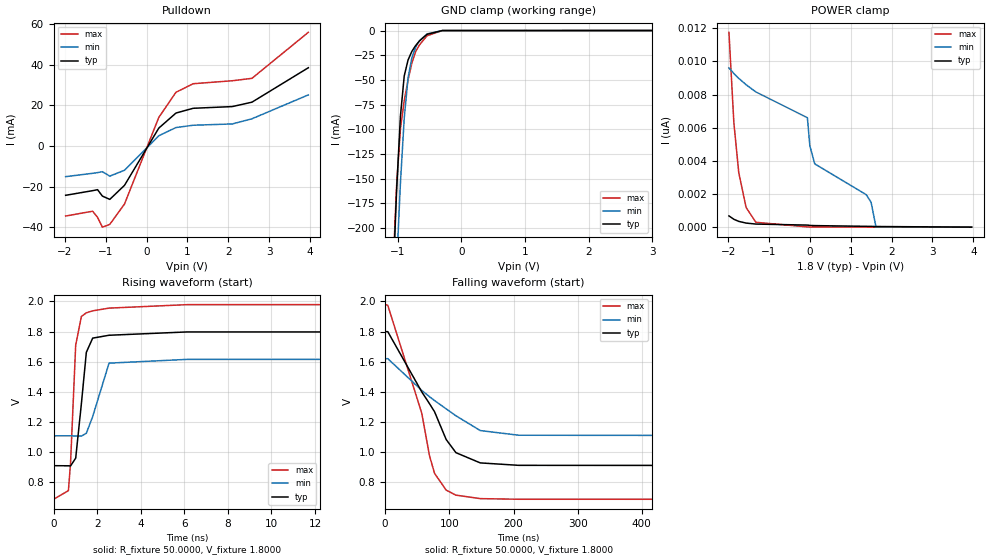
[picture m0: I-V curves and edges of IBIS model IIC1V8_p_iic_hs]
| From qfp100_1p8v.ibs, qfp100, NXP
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[Model] IIC1V8_p_iic_hs
|   Model IIC1V8_p_iic_hs
| This model was characterised for following simulation conditions:
| External (pad) voltage:
|   - Typ: 1.8V,   - Min: 1.62V,   - Max: 1.98V
| Library cells for typ/min/max conditions are connected as defined below:
|  IO - External Pad
|  A - Core Input
|  EN - Output Buffer Enable
|  BOOST - vdde
|  ECS - gnd
|  EGP - gnd
|  ENZI - vdd
|  EPD - gnd
|  EPUN - vdd
|  ZI - NC
|  ZIF - NC
|  gnd - gnd
|  gnde - gnde
|  vdd - vdd
|  vdde - vdde
| All other pins connected to ground
Model_type I/O_open_drain
Polarity   Non-Inverting
Enable   Active-Low
Vinl =   0.5400V
Vinh =   1.2600V
Vmeas =  0.9000V
Cref =   0.0F
Rref =   1000.000
Vref =   1.8000V
C_comp   3.6454pF   3.5038pF   3.7808pF
|C_comp_pullup   0.9524pF   0.9269pF   0.9624pF
|C_comp_pulldown   2.3410pF   2.4924pF   2.1971pF
[Model Spec]
| variable   typ   min   max
Vinh   0.5400V   0.4860V   0.5940V
Vinl   1.2600V   1.1340V   1.3860V
Vmeas   0.9000V   0.8100V   0.9900V
Vref   1.8000V   1.6200V   1.9800V
Cref   0.0F   0.0F   0.0F
Rref   1.0000k   1.0000k   1.0000k
[Temperature Range]   25.0000   0.1250k   -40.0000
[Voltage Range]   1.8000V   1.6200V   1.9800V
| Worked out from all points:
|   slope of the pulldown table from 0 to 0.27 V, typ, clamps not added: 33.4 ohm
|   GND clamp passes 1 mA (typ) near -0.44 V on its own axis
|   rising waveform, R_fixture 50.0000, V_fixture 1.8000: 20-80 % time 321ps typ, 491ps min, 237ps max; typ from 0.911 V to 1.8 V
|   falling waveform, R_fixture 50.0000, V_fixture 1.8000: 20-80 % time 66.9ns typ, 88.7ns min, 48.9ns max; typ from 1.8 V to 0.911 V
[Pulldown]
|Voltage   I(typ)   I(min)   I(max)
-1.98V    -24.22mA   -15.04mA   -34.42mA
-1.32V    -21.94mA   -13.4mA    -32.06mA
-1.2V     -21.45mA   -13.05mA   -35.06mA
-1.08V    -24.63mA   -12.6mA    -39.9mA
-900mV    -26.23mA   -14.78mA   -38.53mA
-540mV    -19.33mA   -11.9mA    -28.53mA
300mV     8.856mA    5.096mA    14.12mA
720mV     16.26mA    9.117mA    26.48mA
1.14V     18.6mA     10.26mA    30.69mA
2.1V      19.45mA    10.9mA     32.16mA
2.58V     21.61mA    13.44mA    33.34mA
3.96V     38.56mA    25.19mA    55.99mA
[GND_clamp]
|Voltage   I(typ)   I(min)   I(max)
-1.98V    -2.104A    -2.075A    -2.136A
-1.08V    -259.3mA   -333mA     -246.9mA
-1.02V    -161.8mA   -238.7mA   -157.1mA
-960mV    -86.74mA   -154.7mA   -99.46mA
-900mV    -45.95mA   -88.82mA   -71.05mA
-840mV    -29.9mA    -47.99mA   -50.25mA
-780mV    -21.15mA   -27.64mA   -32.98mA
-720mV    -15.16mA   -16.87mA   -21.26mA
-660mV    -10.56mA   -10.24mA   -14.56mA
-540mV    -3.788mA   -3.398mA   -5.292mA
-300mV    -15.94uA   -36uA      -16.34uA
3.96V     0A         0A         0A
[POWER_clamp]
|Voltage   I(typ)   I(min)   I(max)
-1.98V    679.6pA    9.61nA     11.76nA
-1.86V    475.2pA    9.277nA    6.313nA
-1.74V    349.2pA    8.982nA    3.292nA
-1.56V    245.6pA    8.597nA    1.186nA
-1.32V    186pA      8.161nA    293.2pA
-60mV     124.8pA    6.606nA    14.31pA
0V        105.5pA    4.916nA    11.81pA
120mV     93.21pA    3.82nA     10.91pA
1.38V     50pA       1.96nA     2.877pA
1.5V      45.28pA    1.501nA    2.149pA
1.62V     39.18pA    0A         1.42pA
3.96V     0A         0A         0A
[Ramp]
| variable   typ   min   max
dV/dt_r  0.5334/0.3209n   0.3066/0.4909n   0.7753/0.2369n
dV/dt_f  0.5334/66.9323n   0.3066/88.7325n   0.7753/48.9497n
R_load = 50.0000
[Rising Waveform]
R_fixture= 50.0000
V_fixture= 1.8000
V_fixture_min= 1.6200
V_fixture_max= 1.9800
|time   V(typ)   V(min)   V(max)
0s        911mV      1.109V     687.8mV
683.3ps   910.2mV    1.109V     745.5mV
780.5ps   909.1mV    1.109V     927.7mV
1.017ns   961.1mV    1.108V     1.71V
1.277ns   1.32V      1.107V     1.9V
1.506ns   1.663V     1.126V     1.925V
1.797ns   1.757V     1.237V     1.938V
2.547ns   1.776V     1.591V     1.956V
6.124ns   1.798V     1.616V     1.979V
1us       1.8V       1.62V      1.98V
[Falling Waveform]
R_fixture= 50.0000
V_fixture= 1.8000
V_fixture_min= 1.6200
V_fixture_max= 1.9800
|time   V(typ)   V(min)   V(max)
0s        1.8V       1.62V      1.98V
4.033ns   1.8V       1.621V     1.975V
57.1ns    1.4V       1.41V      1.258V
68.97ns   1.323V     1.369V     978.6mV
76.93ns   1.269V     1.343V     860.5mV
95.01ns   1.085V     1.288V     749mV
110.3ns   997.3mV    1.242V     715.6mV
148.2ns   929.5mV    1.144V     692.6mV
208ns     913.4mV    1.113V     688.4mV
1us       911.1mV    1.109V     687.9mV
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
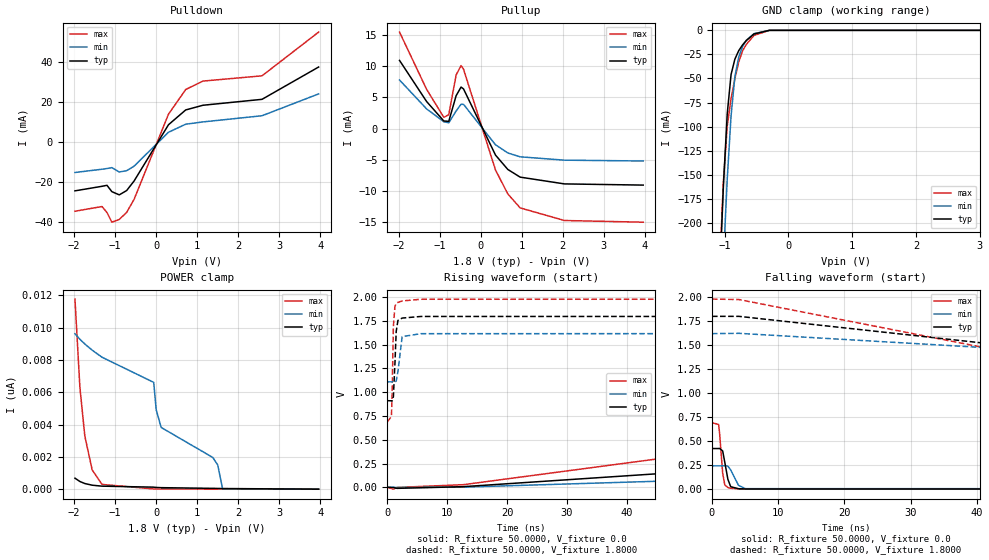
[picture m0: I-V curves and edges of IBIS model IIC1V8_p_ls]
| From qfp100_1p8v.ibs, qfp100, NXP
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[Model] IIC1V8_p_ls
|   Model IIC1V8_p_ls
| This model was characterised for following simulation conditions:
| External (pad) voltage:
|   - Typ: 1.8V,   - Min: 1.62V,   - Max: 1.98V
| Library cells for typ/min/max conditions are connected as defined below:
|  IO - External Pad
|  A - Core Input
|  EN - Output Buffer Enable
|  BOOST - vdde
|  EGP - vdd
|  EHS - gnd
|  ENZI - vdd
|  EPD - gnd
|  EPUN - vdd
|  ZI - NC
|  ZIF - NC
|  gnd - gnd
|  gnde - gnde
|  vdd - vdd
|  vdde - vdde
| All other pins connected to ground
Model_type I/O
Polarity   Non-Inverting
Enable   Active-Low
Vinl =   0.5400V
Vinh =   1.2600V
Vmeas =  0.9000V
Cref =   0.0F
Rref =   1.0000k
Vref =   0.0V
C_comp   3.6452pF   3.5037pF   3.7805pF
|C_comp_pullup   0.9521pF   0.9262pF   0.9623pF
|C_comp_pulldown   2.3411pF   2.4927pF   2.1971pF
[Model Spec]
| variable   typ   min   max
Vinh   0.5400V   0.4860V   0.5940V
Vinl   1.2600V   1.1340V   1.3860V
Vmeas   0.9000V   0.8100V   0.9900V
[Temperature Range]   25.0000   0.1250k   -40.0000
[Voltage Range]   1.8000V   1.6200V   1.9800V
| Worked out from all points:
|   slope of the pulldown table from 0 to 0.27 V, typ, clamps not added: 33.4 ohm
|   slope of the pullup table from 0 to 0.27 V, typ, clamps not added: 80.7 ohm
|   GND clamp passes 1 mA (typ) near -0.44 V on its own axis
|   rising waveform, R_fixture 50.0000, V_fixture 0.0: 20-80 % time 70.1ns typ, 82ns min, 57.1ns max; typ from 0 V to 0.423 V
|   rising waveform, R_fixture 50.0000, V_fixture 1.8000: 20-80 % time 319ps typ, 487ps min, 235ps max; typ from 0.911 V to 1.8 V
|   falling waveform, R_fixture 50.0000, V_fixture 0.0: 20-80 % time 672ps typ, 1.04ns min, 474ps max; typ from 0.423 V to 0 V
|   falling waveform, R_fixture 50.0000, V_fixture 1.8000: 20-80 % time 66.9ns typ, 88.7ns min, 49ns max; typ from 1.8 V to 0.911 V
[Pulldown]
|Voltage   I(typ)   I(min)   I(max)
-1.98V    -24.22mA   -15.04mA   -34.42mA
-1.32V    -21.94mA   -13.4mA    -32.06mA
-1.2V     -21.45mA   -13.05mA   -35.06mA
-1.08V    -24.63mA   -12.6mA    -39.9mA
-900mV    -26.23mA   -14.78mA   -38.53mA
-720mV    -24.07mA   -14.13mA   -34.99mA
-540mV    -19.33mA   -11.9mA    -28.53mA
300mV     8.856mA    5.096mA    14.12mA
720mV     16.26mA    9.117mA    26.48mA
1.14V     18.6mA     10.26mA    30.69mA
2.58V     21.56mA    13.35mA    33.32mA
3.96V     37.73mA    24.28mA    55.2mA
[Pullup]
|Voltage   I(typ)   I(min)   I(max)
-1.98V    10.95mA    7.799mA    15.5mA
-1.32V    4.346mA    3.159mA    6.304mA
-900mV    1.218mA    1.094mA    1.804mA
-780mV    1.156mA    929.2uA    2.224mA
-600mV    5.286mA    2.831mA    8.611mA
-480mV    6.667mA    3.906mA    10.12mA
-420mV    6.372mA    3.889mA    9.539mA
360mV     -4.265mA   -2.608mA   -6.666mA
660mV     -6.57mA    -3.917mA   -10.5mA
960mV     -7.8mA     -4.537mA   -12.74mA
2.04V     -8.889mA   -5.075mA   -14.77mA
3.96V     -9.081mA   -5.209mA   -15.04mA
[GND_clamp]
|Voltage   I(typ)   I(min)   I(max)
-1.98V    -2.104A    -2.075A    -2.136A
-1.08V    -259.3mA   -333mA     -246.9mA
-1.02V    -161.8mA   -238.7mA   -157.1mA
-960mV    -86.74mA   -154.7mA   -99.46mA
-900mV    -45.95mA   -88.82mA   -71.05mA
-840mV    -29.9mA    -47.99mA   -50.25mA
-780mV    -21.15mA   -27.64mA   -32.98mA
-720mV    -15.16mA   -16.87mA   -21.26mA
-660mV    -10.56mA   -10.24mA   -14.56mA
-540mV    -3.788mA   -3.398mA   -5.292mA
-300mV    -15.94uA   -36uA      -16.34uA
3.96V     0A         0A         0A
[POWER_clamp]
|Voltage   I(typ)   I(min)   I(max)
-1.98V    679.6pA    9.61nA     11.76nA
-1.86V    475.2pA    9.277nA    6.313nA
-1.74V    349.2pA    8.982nA    3.292nA
-1.56V    245.6pA    8.597nA    1.186nA
-1.32V    186pA      8.161nA    293.2pA
-60mV     124.8pA    6.606nA    14.31pA
0V        105.5pA    4.916nA    11.81pA
120mV     93.21pA    3.82nA     10.91pA
1.38V     50pA       1.96nA     2.877pA
1.5V      45.28pA    1.501nA    2.149pA
1.62V     39.18pA    0A         1.42pA
3.96V     0A         0A         0A
[Ramp]
| variable   typ   min   max
dV/dt_r  0.2539/70.1178n   0.1457/81.9302n   0.4150/57.0489n
dV/dt_f  0.5334/66.9358n   0.3066/88.6649n   0.7753/48.9538n
R_load = 50.0000
[Rising Waveform]
R_fixture= 50.0000
V_fixture= 0.0
V_fixture_min= 0.0
V_fixture_max= 0.0
|time   V(typ)   V(min)   V(max)
0s        602.8pV    52.95nV    41.9pV
1.012ns   -3.31mV    192.5uV    -19.98mV
1.632ns   -11.39mV   -2.738mV   -1.795mV
12.68ns   6.299mV    1.388mV    27.19mV
45.88ns   145.4mV    64.89mV    304.8mV
84.55ns   285.2mV    143.4mV    561.1mV
103.3ns   339.8mV    172mV      629.2mV
134ns     392.1mV    207.9mV    672.5mV
250.9ns   422.4mV    241.3mV    691.3mV
1us       423.2mV    242.8mV    691.7mV
[Rising Waveform]
R_fixture= 50.0000
V_fixture= 1.8000
V_fixture_min= 1.6200
V_fixture_max= 1.9800
|time   V(typ)   V(min)   V(max)
0s        911mV      1.109V     687.8mV
685.2ps   909.5mV    1.109V     745.1mV
787ps     907.1mV    1.109V     945.8mV
1.007ns   951.3mV    1.108V     1.694V
1.269ns   1.304V     1.105V     1.904V
1.479ns   1.639V     1.118V     1.932V
1.768ns   1.755V     1.218V     1.945V
2.476ns   1.78V      1.585V     1.96V
5.596ns   1.797V     1.616V     1.978V
1us       1.8V       1.62V      1.98V
[Falling Waveform]
R_fixture= 50.0000
V_fixture= 0.0
V_fixture_min= 0.0
V_fixture_max= 0.0
|time   V(typ)   V(min)   V(max)
0s        423.2mV    242.8mV    691.7mV
1.011ns   423.2mV    242.8mV    674.4mV
1.154ns   424.5mV    242.8mV    586.3mV
1.621ns   398.5mV    242.8mV    166.3mV
1.942ns   280.1mV    244.4mV    44.84mV
2.413ns   102.2mV    239.4mV    16.8mV
2.833ns   25.91mV    200.2mV    9.661mV
4.004ns   4.701mV    40.3mV     3.498mV
5.055ns   2.01mV     5.162mV    2.038mV
1us       19.02nV    85.51nV    10.92nV
[Falling Waveform]
R_fixture= 50.0000
V_fixture= 1.8000
V_fixture_min= 1.6200
V_fixture_max= 1.9800
|time   V(typ)   V(min)   V(max)
0s        1.8V       1.62V      1.98V
4.079ns   1.8V       1.623V     1.975V
57.22ns   1.399V     1.41V      1.256V
69.33ns   1.321V     1.367V     971.7mV
77.23ns   1.267V     1.342V     857.4mV
95.69ns   1.079V     1.287V     746.9mV
111ns     994.9mV    1.239V     714.6mV
149.1ns   928.8mV    1.143V     692.4mV
207.1ns   913.6mV    1.113V     688.4mV
1us       911.1mV    1.109V     687.9mV
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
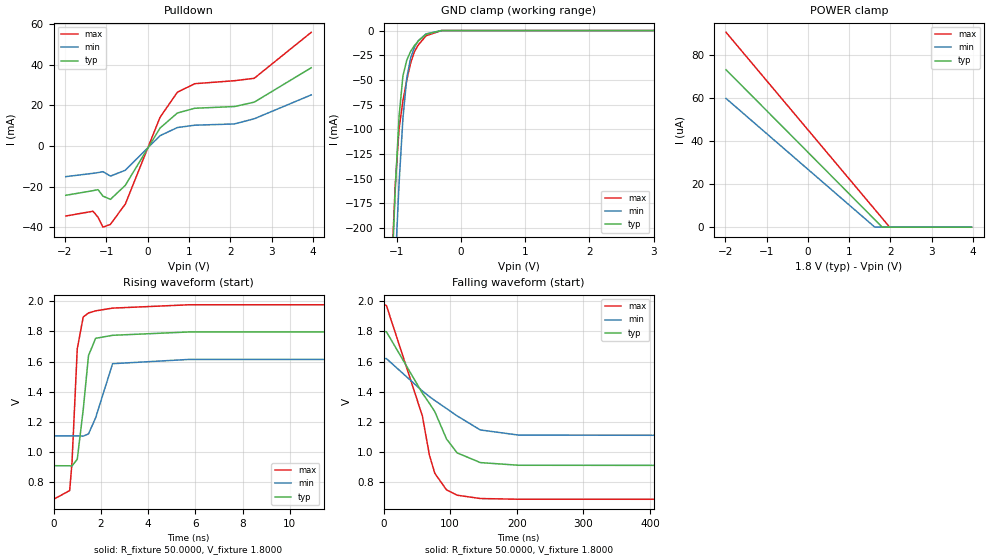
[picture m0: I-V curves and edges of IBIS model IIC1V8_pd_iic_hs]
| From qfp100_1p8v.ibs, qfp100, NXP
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[Model] IIC1V8_pd_iic_hs
|   Model IIC1V8_pd_iic_hs
| This model was characterised for following simulation conditions:
| External (pad) voltage:
|   - Typ: 1.8V,   - Min: 1.62V,   - Max: 1.98V
| Library cells for typ/min/max conditions are connected as defined below:
|  IO - External Pad
|  A - Core Input
|  EN - Output Buffer Enable
|  BOOST - vdde
|  ECS - gnd
|  EGP - gnd
|  ENZI - vdd
|  EPD - vdd
|  EPUN - vdd
|  ZI - NC
|  ZIF - NC
|  gnd - gnd
|  gnde - gnde
|  vdd - vdd
|  vdde - vdde
| All other pins connected to ground
Model_type I/O_open_drain
Polarity   Non-Inverting
Enable   Active-Low
Vinl =   0.5400V
Vinh =   1.2600V
Vmeas =  0.9000V
Cref =   0.0F
Rref =   1000.000
Vref =   1.8000V
C_comp   3.6138pF   3.4666pF   3.7547pF
|C_comp_pullup   0.9378pF   0.9163pF   0.9441pF
|C_comp_pulldown   2.3253pF   2.4781pF   2.1797pF
[Model Spec]
| variable   typ   min   max
Vinh   0.5400V   0.4860V   0.5940V
Vinl   1.2600V   1.1340V   1.3860V
Vmeas   0.9000V   0.8100V   0.9900V
Vref   1.8000V   1.6200V   1.9800V
Cref   0.0F   0.0F   0.0F
Rref   1.0000k   1.0000k   1.0000k
[Temperature Range]   25.0000   0.1250k   -40.0000
[Voltage Range]   1.8000V   1.6200V   1.9800V
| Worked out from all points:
|   slope of the pulldown table from 0 to 0.27 V, typ, clamps not added: 33.4 ohm
|   GND clamp passes 1 mA (typ) near -0.44 V on its own axis
|   rising waveform, R_fixture 50.0000, V_fixture 1.8000: 20-80 % time 320ps typ, 490ps min, 236ps max; typ from 0.91 V to 1.8 V
|   falling waveform, R_fixture 50.0000, V_fixture 1.8000: 20-80 % time 66.8ns typ, 88.6ns min, 48.9ns max; typ from 1.8 V to 0.91 V
[Pulldown]
|Voltage   I(typ)   I(min)   I(max)
-1.98V    -24.22mA   -15.04mA   -34.42mA
-1.32V    -21.94mA   -13.4mA    -32.06mA
-1.2V     -21.45mA   -13.05mA   -35.06mA
-1.08V    -24.63mA   -12.6mA    -39.9mA
-900mV    -26.23mA   -14.78mA   -38.53mA
-540mV    -19.33mA   -11.9mA    -28.53mA
300mV     8.856mA    5.096mA    14.12mA
720mV     16.26mA    9.117mA    26.48mA
1.14V     18.6mA     10.26mA    30.69mA
2.1V      19.45mA    10.89mA    32.16mA
2.58V     21.61mA    13.43mA    33.34mA
3.96V     38.53mA    25.17mA    55.97mA
[GND_clamp]
|Voltage   I(typ)   I(min)   I(max)
-1.98V    -2.104A    -2.075A    -2.136A
-1.08V    -259.3mA   -333mA     -246.9mA
-1.02V    -161.8mA   -238.7mA   -157.1mA
-960mV    -86.75mA   -154.7mA   -99.47mA
-900mV    -45.96mA   -88.82mA   -71.06mA
-840mV    -29.91mA   -48mA      -50.26mA
-780mV    -21.16mA   -27.65mA   -32.99mA
-720mV    -15.17mA   -16.88mA   -21.27mA
-660mV    -10.57mA   -10.24mA   -14.57mA
-540mV    -3.796mA   -3.405mA   -5.301mA
-300mV    -21.69uA   -40.85uA   -23.15uA
3.96V     0A         0A         0A
[POWER_clamp]
|Voltage   I(typ)   I(min)   I(max)
-1.98V    73.06uA    59.72uA    90.42uA
1.62V     3.484uA    0A         8.225uA
1.8V      0A         0A         4.113uA
1.98V     0A         0A         0A
3.96V     0A         0A         0A
[Ramp]
| variable   typ   min   max
dV/dt_r  0.5328/0.3204n   0.3064/0.4905n   0.7742/0.2363n
dV/dt_f  0.5327/66.8167n   0.3063/88.5485n   0.7742/48.8803n
R_load = 50.0000
[Rising Waveform]
R_fixture= 50.0000
V_fixture= 1.8000
V_fixture_min= 1.6200
V_fixture_max= 1.9800
|time   V(typ)   V(min)   V(max)
0s        910.3mV    1.108V     687.5mV
683.8ps   909.5mV    1.108V     745.6mV
781ps     908.4mV    1.108V     928.7mV
1.004ns   952.7mV    1.108V     1.684V
1.256ns   1.281V     1.106V     1.895V
1.48ns    1.64V      1.121V     1.922V
1.782ns   1.754V     1.228V     1.936V
2.499ns   1.774V     1.586V     1.954V
5.711ns   1.796V     1.614V     1.976V
1us       1.798V     1.619V     1.978V
[Falling Waveform]
R_fixture= 50.0000
V_fixture= 1.8000
V_fixture_min= 1.6200
V_fixture_max= 1.9800
|time   V(typ)   V(min)   V(max)
0s        1.798V     1.619V     1.978V
4.099ns   1.798V     1.62V      1.972V
58.16ns   1.391V     1.405V     1.24V
68.8ns    1.323V     1.368V     979.5mV
76.88ns   1.268V     1.342V     859.4mV
94.48ns   1.087V     1.289V     749.9mV
110.4ns   995.3mV    1.24V      714.9mV
145.3ns   930.8mV    1.147V     692.8mV
202.8ns   913.2mV    1.113V     688.1mV
1us       910.4mV    1.108V     687.5mV
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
